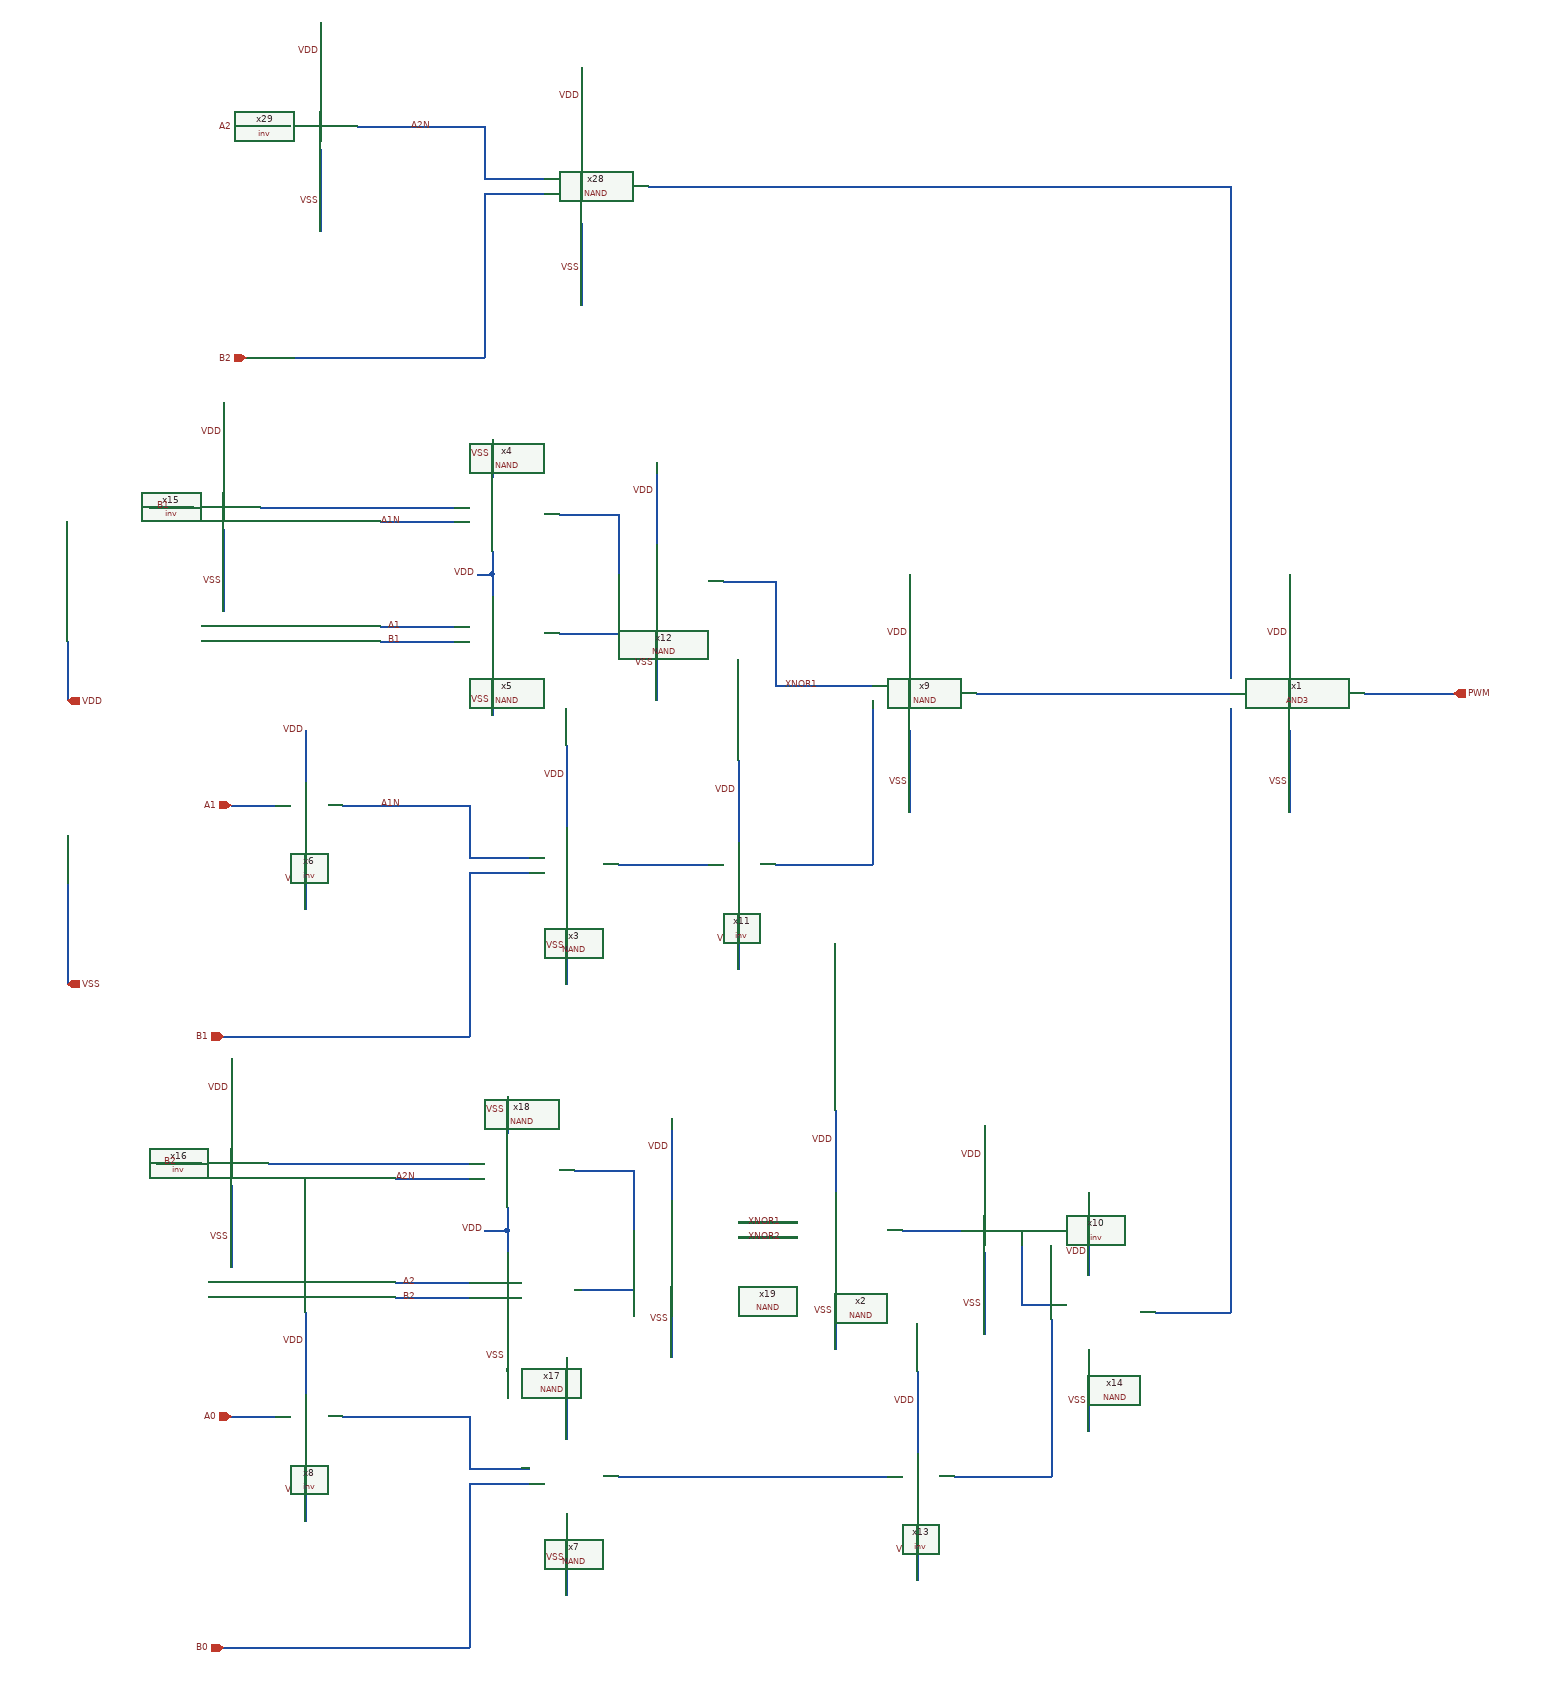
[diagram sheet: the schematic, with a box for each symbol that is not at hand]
v {xschem version=3.4.6 file_version=1.2}
G {}
K {}
V {}
S {}
E {}
N 1270 -3310 1270 -3230 {lab=VDD}
N 1270 -3050 1270 -2850 {lab=VSS}
N 1510 -4000 1570 -4000 {lab=A2}
N 1960 -4080 1960 -3970 {lab=VDD}
N 1960 -3870 1960 -3760 {lab=VSS}
N 1830 -3910 1830 -3690 {lab=B2}
N 1830 -3910 1910 -3910 {lab=B2}
N 1610 -3970 1610 -3860 {lab=VSS}
N 1610 -4140 1610 -4030 {lab=VDD}
N 1830 -4000 1830 -3930 {lab=A2N}
N 1660 -4000 1830 -4000 {lab=A2N}
N 1830 -3930 1910 -3930 {lab=A2N}
N 1500 -3690 1830 -3690 {lab=B2}
N 1490 -3090 1550 -3090 {lab=A1}
N 1940 -3170 1940 -3060 {lab=VDD}
N 1940 -2960 1940 -2850 {lab=VSS}
N 1810 -3000 1810 -2780 {lab=B1}
N 1810 -3000 1890 -3000 {lab=B1}
N 1590 -3060 1590 -2950 {lab=VSS}
N 1810 -3090 1810 -3020 {lab=A1N}
N 1640 -3090 1810 -3090 {lab=A1N}
N 1810 -3020 1890 -3020 {lab=A1N}
N 1480 -2780 1810 -2780 {lab=B1}
N 1490 -2270 1550 -2270 {lab=A0}
N 2010 -2190 2370 -2190 {lab=#net1}
N 1940 -2350 1940 -2240 {lab=VDD}
N 1940 -2140 1940 -2030 {lab=VSS}
N 1810 -2180 1810 -1960 {lab=B0}
N 1810 -2180 1890 -2180 {lab=B0}
N 1590 -2240 1590 -2130 {lab=VSS}
N 1590 -2410 1590 -2300 {lab=VDD}
N 1810 -2270 1810 -2200 {lab=#net2}
N 1640 -2270 1810 -2270 {lab=#net2}
N 1810 -2200 1890 -2200 {lab=#net2}
N 1480 -1960 1810 -1960 {lab=B0}
N 2910 -3190 2910 -3080 {lab=VSS}
N 2910 -3400 2910 -3290 {lab=VDD}
N 3010 -3240 3130 -3240 {lab=PWM}
N 2010 -3010 2130 -3010 {lab=#net3}
N 1690 -3330 1790 -3330 {lab=A1}
N 1690 -3310 1790 -3310 {lab=B1}
N 2170 -2980 2170 -2870 {lab=VSS}
N 2170 -3150 2170 -3040 {lab=VDD}
N 2410 -2160 2410 -2050 {lab=VSS}
N 2410 -2330 2410 -2220 {lab=VDD}
N 2350 -3230 2350 -3010 {lab=#net4}
N 2220 -3010 2350 -3010 {lab=#net4}
N 2460 -2190 2590 -2190 {lab=#net5}
N 2590 -2400 2590 -2190 {lab=#net5}
N 2730 -2410 2830 -2410 {lab=#net6}
N 2490 -3240 2830 -3240 {lab=#net7}
N 2400 -3190 2400 -3080 {lab=VSS}
N 2400 -3400 2400 -3290 {lab=VDD}
N 2640 -2360 2640 -2250 {lab=VSS}
N 2640 -2570 2640 -2460 {lab=VDD}
N 1840 -3400 1840 -3370 {lab=VDD}
N 1840 -3270 1840 -3210 {lab=VSS}
N 1840 -3580 1840 -3530 {lab=VSS}
N 1930 -3480 2010 -3480 {lab=#net8}
N 2010 -3480 2010 -3400 {lab=#net8}
N 1930 -3320 2010 -3320 {lab=#net9}
N 2010 -3380 2010 -3320 {lab=#net9}
N 1690 -3470 1790 -3470 {lab=A1N}
N 1380 -3490 1440 -3490 {lab=B1}
N 1480 -3460 1480 -3350 {lab=VSS}
N 1480 -3630 1480 -3520 {lab=VDD}
N 1390 -2610 1450 -2610 {lab=B2}
N 1490 -2580 1490 -2470 {lab=VSS}
N 1490 -2750 1490 -2640 {lab=VDD}
N 1710 -2450 1810 -2450 {lab=A2}
N 1710 -2430 1810 -2430 {lab=B2}
N 1860 -2520 1860 -2490 {lab=VDD}
N 1860 -2390 1860 -2330 {lab=VSS}
N 1860 -2700 1860 -2650 {lab=VSS}
N 1950 -2600 2030 -2600 {lab=#net10}
N 2030 -2600 2030 -2520 {lab=#net10}
N 1950 -2440 2030 -2440 {lab=#net11}
N 2030 -2500 2030 -2440 {lab=#net11}
N 1710 -2590 1810 -2590 {lab=A2N}
N 2080 -2670 2080 -2560 {lab=VDD}
N 2080 -2460 2080 -2350 {lab=VSS}
N 2060 -3550 2060 -3440 {lab=VDD}
N 2060 -3340 2060 -3230 {lab=VSS}
N 2150 -3390 2220 -3390 {lab=XNOR1}
N 2170 -2510 2250 -2510 {lab=XNOR2}
N 2830 -3920 2830 -3260 {lab=#net12}
N 2050 -3920 2830 -3920 {lab=#net12}
N 1590 -3190 1590 -3120 {lab=VDD}
N 2220 -3390 2220 -3250 {lab=XNOR1}
N 2220 -3250 2350 -3250 {lab=XNOR1}
N 2830 -3220 2830 -2410 {lab=#net6}
N 1830 -2520 1860 -2520 {lab=VDD}
N 1860 -2550 1860 -2520 {lab=VDD}
N 1820 -3400 1840 -3400 {lab=VDD}
N 1840 -3430 1840 -3400 {lab=VDD}
N 1530 -3490 1790 -3490 {lab=#net13}
N 1540 -2610 1810 -2610 {lab=#net14}
N 2300 -2680 2300 -2570 {lab=VDD}
N 2300 -2470 2300 -2360 {lab=VSS}
N 2390 -2520 2470 -2520 {lab=#net15}
N 2170 -2530 2250 -2530 {lab=XNOR1}
N 2500 -2490 2500 -2380 {lab=VSS}
N 2500 -2660 2500 -2550 {lab=VDD}
N 2550 -2520 2550 -2420 {lab=#net16}
N 2550 -2420 2590 -2420 {lab=#net16}
C {iopin.sym} 1270 -3230 0 1 {name=p92 lab=VDD}
C {iopin.sym} 1270 -2850 0 1 {name=p93 lab=VSS}
C {ipin.sym} 1510 -4000 0 0 {name=p94 lab=A2}
C {lab_wire.sym} 1960 -4040 0 0 {name=p105 sig_type=std_logic lab=VDD}
C {NAND.sym} 2030 -3830 0 0 {name=x28}
C {lab_wire.sym} 1610 -3900 0 0 {name=p106 sig_type=std_logic lab=VSS
}
C {lab_wire.sym} 1610 -4100 0 0 {name=p107 sig_type=std_logic lab=VDD}
C {inv.sym} 1650 -3910 0 0 {name=x29}
C {lab_wire.sym} 1940 -3130 0 0 {name=p8 sig_type=std_logic lab=VDD}
C {NAND.sym} 2010 -2920 0 0 {name=x3}
C {lab_wire.sym} 1590 -2990 0 0 {name=p9 sig_type=std_logic lab=VSS
}
C {lab_wire.sym} 1590 -3190 0 0 {name=p10 sig_type=std_logic lab=VDD}
C {lab_wire.sym} 1940 -2310 0 0 {name=p20 sig_type=std_logic lab=VDD}
C {NAND.sym} 2010 -2100 0 0 {name=x7}
C {lab_wire.sym} 1590 -2170 0 0 {name=p21 sig_type=std_logic lab=VSS
}
C {lab_wire.sym} 1590 -2370 0 0 {name=p22 sig_type=std_logic lab=VDD}
C {inv.sym} 1630 -2180 0 0 {name=x8}
C {lab_wire.sym} 1960 -3810 0 0 {name=p1 sig_type=std_logic lab=VSS
}
C {lab_wire.sym} 1940 -2900 0 0 {name=p3 sig_type=std_logic lab=VSS
}
C {lab_wire.sym} 1940 -2080 0 0 {name=p4 sig_type=std_logic lab=VSS
}
C {AND3.sym} 2910 -3240 0 0 {name=x1}
C {lab_wire.sym} 2910 -3120 0 0 {name=p7 sig_type=std_logic lab=VSS}
C {lab_wire.sym} 2910 -3320 0 0 {name=p16 sig_type=std_logic lab=VDD
}
C {ipin.sym} 1510 -3690 0 0 {name=p17 lab=B2}
C {ipin.sym} 1490 -3090 0 0 {name=p19 lab=A1}
C {ipin.sym} 1480 -2780 0 0 {name=p23 lab=B1}
C {ipin.sym} 1480 -1960 0 0 {name=p25 lab=B0}
C {ipin.sym} 1490 -2270 0 0 {name=p26 lab=A0}
C {opin.sym} 3130 -3240 0 0 {name=p27 lab=PWM}
C {NAND.sym} 1910 -3230 0 0 {name=x5}
C {lab_wire.sym} 1720 -3330 0 0 {name=p14 sig_type=std_logic lab=A1}
C {lab_wire.sym} 1720 -3310 0 0 {name=p15 sig_type=std_logic lab=B1}
C {inv.sym} 1630 -3000 0 0 {name=x6}
C {NAND.sym} 2470 -3150 0 0 {name=x9}
C {lab_wire.sym} 2170 -2910 0 0 {name=p28 sig_type=std_logic lab=VSS
}
C {lab_wire.sym} 2170 -3110 0 0 {name=p29 sig_type=std_logic lab=VDD}
C {inv.sym} 2210 -2920 0 0 {name=x11}
C {lab_wire.sym} 2410 -2090 0 0 {name=p32 sig_type=std_logic lab=VSS
}
C {lab_wire.sym} 2410 -2290 0 0 {name=p33 sig_type=std_logic lab=VDD}
C {inv.sym} 2450 -2100 0 0 {name=x13}
C {NAND.sym} 2710 -2320 0 0 {name=x14}
C {lab_wire.sym} 2400 -3120 0 0 {name=p34 sig_type=std_logic lab=VSS}
C {lab_wire.sym} 2400 -3320 0 0 {name=p35 sig_type=std_logic lab=VDD
}
C {lab_wire.sym} 2640 -2290 0 0 {name=p36 sig_type=std_logic lab=VSS}
C {lab_wire.sym} 2640 -2490 0 0 {name=p37 sig_type=std_logic lab=VDD
}
C {NAND.sym} 1910 -3570 2 1 {name=x4}
C {lab_wire.sym} 1840 -3560 0 0 {name=p12 sig_type=std_logic lab=VSS
}
C {lab_wire.sym} 1840 -3230 0 0 {name=p13 sig_type=std_logic lab=VSS
}
C {lab_wire.sym} 1820 -3400 0 0 {name=p30 sig_type=std_logic lab=VDD}
C {lab_wire.sym} 1720 -3090 0 0 {name=p31 sig_type=std_logic lab=A1N}
C {lab_wire.sym} 1760 -4000 0 0 {name=p38 sig_type=std_logic lab=A2N}
C {NAND.sym} 2130 -3300 0 0 {name=x12}
C {lab_wire.sym} 1720 -3470 0 0 {name=p39 sig_type=std_logic lab=A1N}
C {lab_wire.sym} 1480 -3390 0 0 {name=p40 sig_type=std_logic lab=VSS
}
C {lab_wire.sym} 1480 -3590 0 0 {name=p41 sig_type=std_logic lab=VDD}
C {inv.sym} 1520 -3400 0 0 {name=x15}
C {lab_wire.sym} 1490 -2510 0 0 {name=p45 sig_type=std_logic lab=VSS
}
C {lab_wire.sym} 1490 -2710 0 0 {name=p46 sig_type=std_logic lab=VDD}
C {inv.sym} 1530 -2520 0 0 {name=x16}
C {NAND.sym} 1930 -2350 0 0 {name=x17}
C {lab_wire.sym} 1740 -2450 0 0 {name=p49 sig_type=std_logic lab=A2}
C {lab_wire.sym} 1740 -2430 0 0 {name=p50 sig_type=std_logic lab=B2}
C {NAND.sym} 1930 -2690 2 1 {name=x18}
C {lab_wire.sym} 1860 -2680 0 0 {name=p51 sig_type=std_logic lab=VSS
}
C {lab_wire.sym} 1860 -2350 0 0 {name=p52 sig_type=std_logic lab=VSS
}
C {lab_wire.sym} 1830 -2520 0 0 {name=p53 sig_type=std_logic lab=VDD}
C {NAND.sym} 2150 -2420 0 0 {name=x19}
C {lab_wire.sym} 1740 -2590 0 0 {name=p54 sig_type=std_logic lab=A2N}
C {lab_wire.sym} 2080 -2630 0 0 {name=p56 sig_type=std_logic lab=VDD}
C {lab_wire.sym} 2080 -2400 0 0 {name=p57 sig_type=std_logic lab=VSS
}
C {lab_wire.sym} 2060 -3510 0 0 {name=p58 sig_type=std_logic lab=VDD}
C {lab_wire.sym} 2060 -3280 0 0 {name=p59 sig_type=std_logic lab=VSS
}
C {lab_wire.sym} 1420 -2610 0 0 {name=p18 sig_type=std_logic lab=B2}
C {lab_wire.sym} 1410 -3490 0 0 {name=p24 sig_type=std_logic lab=B1}
C {lab_wire.sym} 2280 -3250 0 0 {name=p2 sig_type=std_logic lab=XNOR1}
C {lab_wire.sym} 2230 -2510 0 0 {name=p5 sig_type=std_logic lab=XNOR2}
C {NAND.sym} 2370 -2430 0 0 {name=x2}
C {lab_wire.sym} 2300 -2640 0 0 {name=p6 sig_type=std_logic lab=VDD}
C {lab_wire.sym} 2300 -2410 0 0 {name=p11 sig_type=std_logic lab=VSS
}
C {lab_wire.sym} 2230 -2530 0 0 {name=p43 sig_type=std_logic lab=XNOR1}
C {lab_wire.sym} 2500 -2420 0 0 {name=p42 sig_type=std_logic lab=VSS
}
C {lab_wire.sym} 2500 -2620 0 0 {name=p44 sig_type=std_logic lab=VDD}
C {inv.sym} 2540 -2430 0 0 {name=x10}
